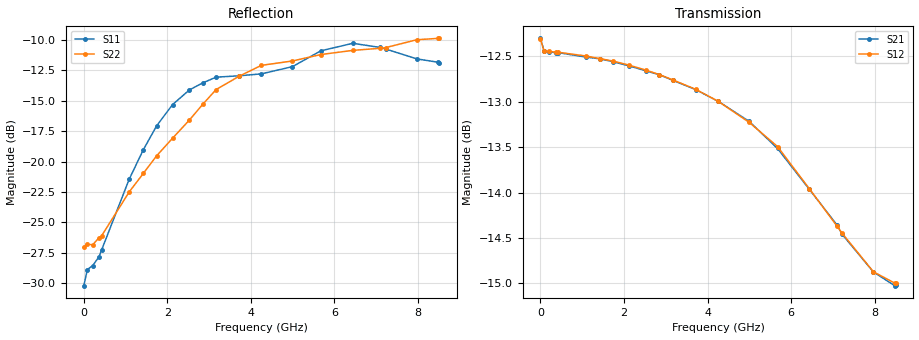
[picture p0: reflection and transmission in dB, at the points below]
! device id: pe43620
! dir: c:\dsa\pe43620\data\pe43620\025c\3p300v\12p00db
! Serial: 1001
! Insertion: A
! Temp: 25C
! VDD: 3.300V
! Attenuation Step: 12.00dB
! IDD: 8.960927e-03mA
! FILE NAME
! DATE 10-22-2008 14:03:46
! CORRECTED  DATA
#  Hz  S  RI  R  50.00
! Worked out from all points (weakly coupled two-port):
!   401 points, 300 kHz to 8.5 GHz, reference 50 ohm
!   highest |S21| = -12.31 dB at 300 kHz (marker M1); lowest = -15.0 dB at 8.479 GHz (marker M2)
!   lowest |S11| = -30.2 dB at 300 kHz (marker M3), VSWR 1.06, Z = 47 - j0.0186 ohm
!   |S11| at or under -10 dB: start of sweep to end of sweep
!   |S22| runs from -27.1 to -9.8 dB; largest |S21 - S12| = 0.00097
!   S11 on the Smith chart (normalised r, x): 300 kHz: 0.94, -0.00; 3.719 GHz: 0.67, -0.19; 7.225 GHz: 0.55, +0.05; 8.5 GHz: 0.63, +0.19
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300000  -0.0309 -0.000198  0.2425 -0.000531  0.2423 -0.000159  -0.0444 -9.53e-05
8.5297e7  -0.0359 -0.00276  0.2386 -0.00394  0.2386 -0.00382  -0.0455 -0.00345
2.127925e8  -0.037 -0.00524  0.2383 -0.00847  0.2384 -0.00833  -0.0448 -0.00822
3.615373e8  -0.0396 -0.00882  0.2377 -0.014  0.2379 -0.014  -0.0465 -0.0139
4.25285e8  -0.042 -0.0105  0.2376 -0.0163  0.2377 -0.0165  -0.0467 -0.0164
1.084012e9  -0.0745 -0.0397  0.2332 -0.0413  0.2335 -0.0415  -0.0601 -0.0447
1.424e9  -0.0956 -0.0579  0.2299 -0.0546  0.23 -0.0545  -0.0714 -0.0537
1.742739e9  -0.1139 -0.0816  0.2258 -0.0666  0.226 -0.0666  -0.0829 -0.0653
2.125225e9  -0.1333 -0.1078  0.2197 -0.0811  0.22 -0.0809  -0.1003 -0.0741
2.528961e9  -0.1485 -0.1293  0.2123 -0.0953  0.2125 -0.0954  -0.1252 -0.0792
2.8477e9  -0.157 -0.1401  0.2059 -0.106  0.206 -0.1059  -0.1493 -0.0851
3.166438e9  -0.1678 -0.1455  0.1988 -0.1156  0.1986 -0.1162  -0.1707 -0.0994
3.718919e9  -0.1816 -0.1328  0.185 -0.132  0.1853 -0.1317  -0.1968 -0.1072
4.25015e9  -0.2033 -0.1057  0.1711 -0.1445  0.1711 -0.1445  -0.2228 -0.1097
4.993874e9  -0.2383 -0.0582  0.151 -0.1577  0.1503 -0.158  -0.2441 -0.0861
5.67385e9  -0.2831 -0.0324  0.1285 -0.1673  0.1287 -0.1678  -0.2704 -0.0507
6.438823e9  -0.3059 -0.00264  0.1023 -0.1722  0.1024 -0.1723  -0.2861 -0.00236
7.09755e9  -0.2924 0.0312  0.0793 -0.1743  0.0789 -0.1742  -0.288 0.0476
7.225045e9  -0.2872 0.0395  0.075 -0.1737  0.0747 -0.1741  -0.2874 0.0604
7.968769e9  -0.2464 0.095  0.0555 -0.1717  0.0553 -0.1718  -0.2973 0.1082
8.478751e9  -0.2155 0.1377  0.0466 -0.1711  0.047 -0.1716  -0.2892 0.1383
8.5e9  -0.2114 0.14  0.0464 -0.1713  0.0464 -0.1718  -0.2881 0.1404
